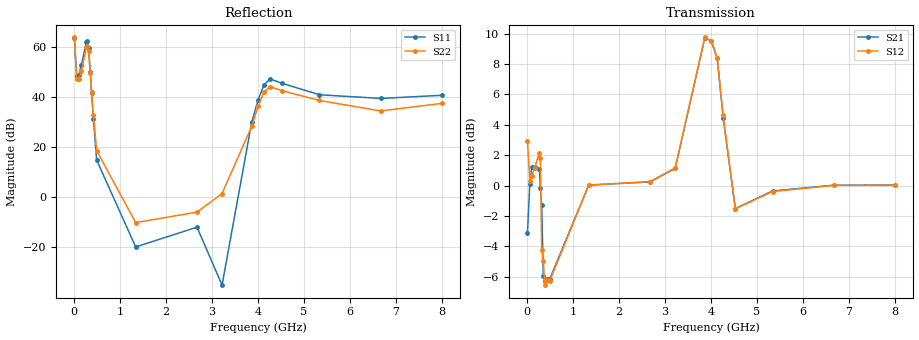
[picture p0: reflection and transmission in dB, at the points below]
!Agilent Technologies,N5230A,US43500312,A.07.50.67
!Agilent N5230A: A.07.50.67
!Date: Tuesday, June 09, 2015 15:36:36
!Correction: S11(Full 2 Port(1,2))
!S21(Full 2 Port(1,2))
!S12(Full 2 Port(1,2))
!S22(Full 2 Port(1,2))
!S2P File: Measurements: S11, S21, S12, S22:
# Hz S  MA  R 50
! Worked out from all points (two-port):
!   1601 points, 10 MHz to 8 GHz, reference 50 ohm
!   highest |S21| = 9.72 dB at 3.865 GHz (marker M1); lowest = -6.3 dB at 384.5 MHz (marker M2)
!   |S21| within 3 dB of the highest: 3.657 GHz to 4.204 GHz (547.2 MHz wide, 13.9 % of centre)
!   lowest |S11| = -35.0 dB at 3.221 GHz (marker M3), VSWR 1.04, Z = 48.6 + j1.01 ohm
!   |S11| at or under -10 dB: 815.9 MHz to 2.101 GHz (1.285 GHz wide, 88.1 % of centre); 2.463 GHz to 2.7 GHz (237.7 MHz wide, 9.21 % of centre); 3.165 GHz to 3.262 GHz (97.05 MHz wide, 3.02 % of centre)
!   |S22| runs from -13.8 to 63.6 dB; largest |S21 - S12| = 0.99
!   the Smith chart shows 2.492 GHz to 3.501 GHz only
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1e7  1497 171.1  0.696 17.8  1.399 -23.2  1521 -19.4
5.99375e7  256.5 326.7  1.01 -0.4  1.034 10.1  230.4 92.5
1.048812e8  275.6 369.5  1.155 0.9  1.076 -4.6  227.1 113.2
1.648062e8  431.4 403.4  1.154 1.2  1.143 -0.5  327.3 125.0
2.69675e8  1221 387.8  1.137 7.0  1.283 3.5  960.1 104.4
2.8965e8  1291 402.8  0.9785 19.4  1.231 18.9  1043 121.5
3.196125e8  941 427.8  0.8637 27.4  0.6129 25.3  807.3 150.9
3.545688e8  317.9 445.5  0.5047 23.1  0.5666 20.0  300.7 177.3
3.845312e8  120 442.0  0.4866 17.0  0.4702 15.9  125.3 184.2
4.244812e8  35.53 436.3  0.4919 17.5  0.4887 16.6  43.67 197.7
4.943938e8  5.507 419.5  0.4926 28.4  0.4857 28.7  8.463 231.5
1.343331e9  0.1025 856.5  1.004 32.9  1.004 32.9  0.3129 764.9
2.676662e9  0.2532 1041.2  1.028 34.6  1.031 34.7  0.5047 1223.6
3.220981e9  0.01779 1224.3  1.139 51.7  1.143 51.9  1.179 1374.0
3.865175e9  30.8 1416.0  3.063 30.7  3.075 30.9  25.84 1535.7
4.005e9  86.92 1408.6  2.991 9.2  2.996 9.5  64.32 1525.2
4.134838e9  174.4 1384.6  2.632 -14.5  2.627 -14.4  124.8 1497.3
4.264675e9  225.4 1351.3  1.675 -34.2  1.705 -34.5  158.4 1460.4
4.529344e9  184.9 1321.8  0.84 -12.4  0.8385 -12.8  131.8 1425.2
5.338331e9  109.7 1327.2  0.9598 5.4  0.9557 5.0  84.35 1403.7
6.671662e9  92.65 1362.2  1.003 4.5  1.001 4.6  52.14 1343.0
8e9  107 1388.9  1.004 3.8  1.002 3.8  73.68 1309.9
